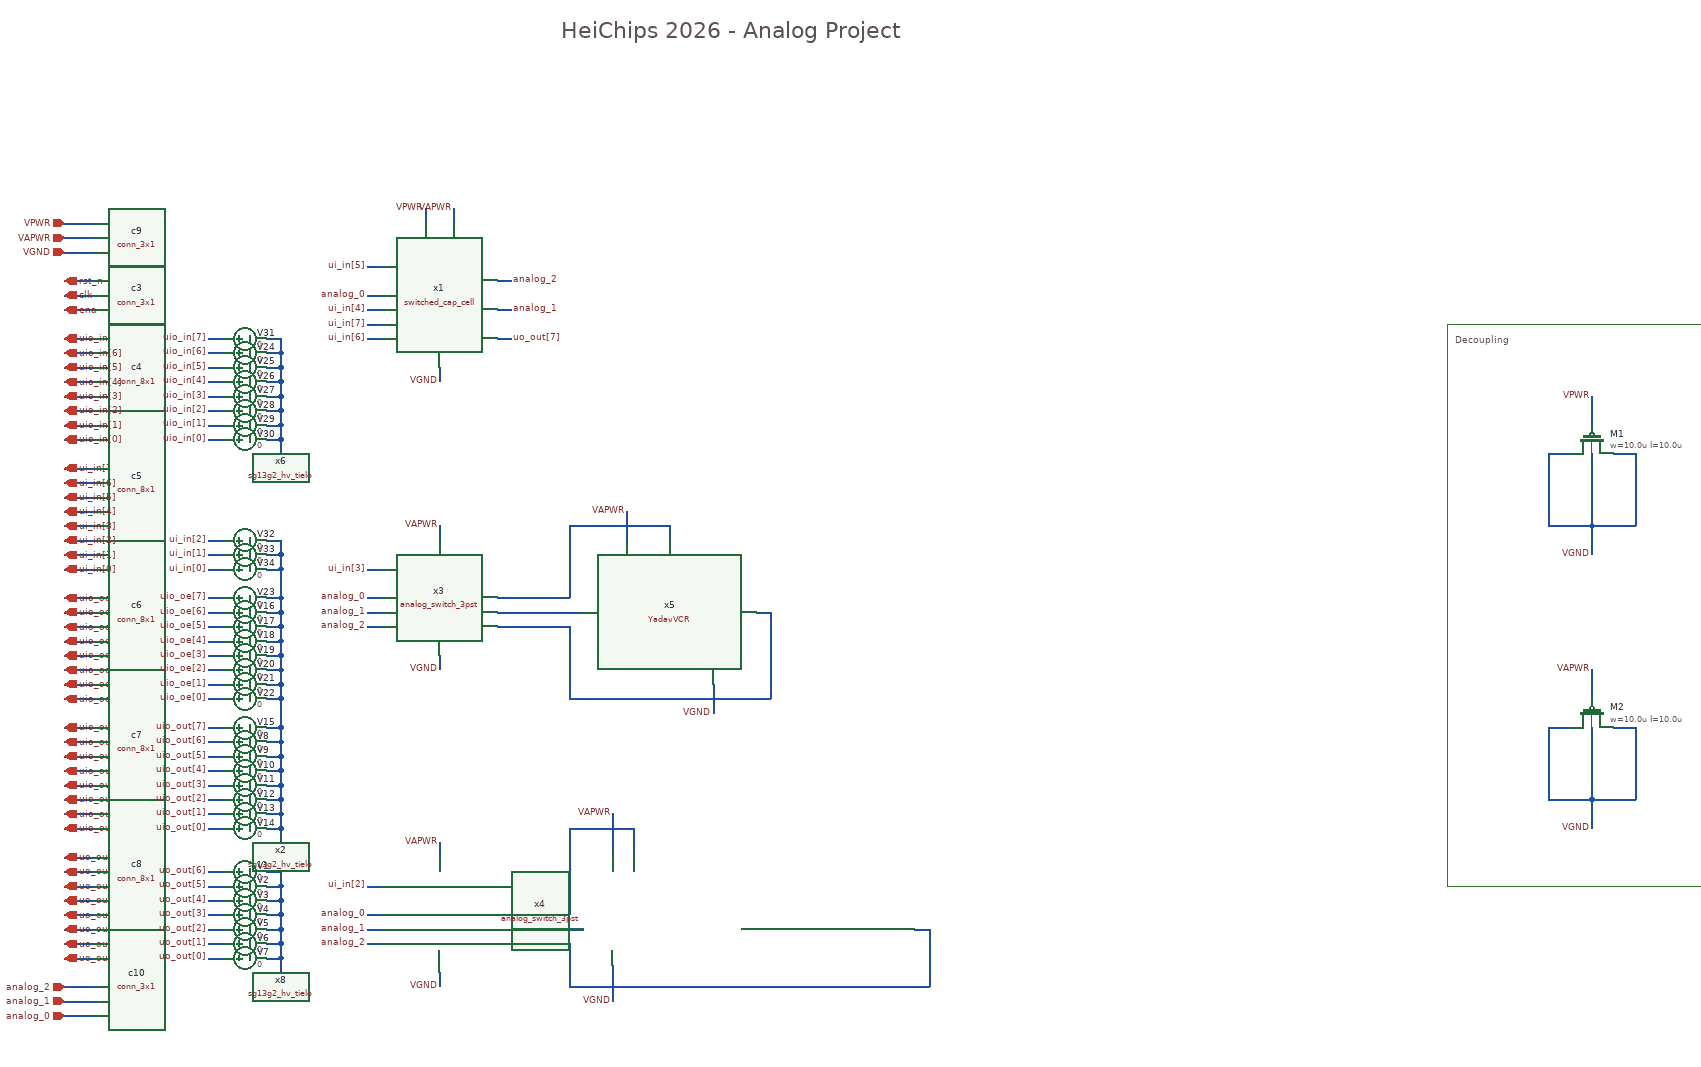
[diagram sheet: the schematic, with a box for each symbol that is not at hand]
v {xschem version=3.4.8RC file_version=1.3}
G {}
K {}
V {}
S {}
F {}
E {}
P 4 1 2050 -1280 {}
P 4 5 2060 -1280 2460 -1280 2460 -500 2060 -500 2060 -1280 {fill = false
dash = 16}
T {HeiChips 2026 - Analog Project} 830 -1700 0 0 1 1 {}
T {Decoupling} 2070 -1270 0 0 0.4 0.4 {}
N 2260 -800 2260 -760 {lab=VAPWR
spice_ignore=true}
N 2200 -720 2230 -720 {lab=VGND
spice_ignore=true}
N 2200 -720 2200 -620 {lab=VGND
spice_ignore=true}
N 2260 -620 2320 -620 {lab=VGND
spice_ignore=true}
N 2320 -720 2320 -620 {lab=VGND
spice_ignore=true}
N 2290 -720 2320 -720 {lab=VGND
spice_ignore=true}
N 2260 -620 2260 -580 {lab=VGND
spice_ignore=true}
N 2260 -720 2260 -620 {lab=VGND
spice_ignore=true}
N 2200 -620 2260 -620 {lab=VGND
spice_ignore=true}
N 140 -1320 180 -1320 {lab=clk}
N 140 -1300 180 -1300 {lab=ena}
N 140 -1340 180 -1340 {lab=rst_n}
N 140 -1260 180 -1260 {lab=uio_in[7]}
N 140 -1240 180 -1240 {lab=uio_in[6]}
N 140 -1220 180 -1220 {lab=uio_in[5]}
N 140 -1200 180 -1200 {lab=uio_in[4]}
N 140 -1180 180 -1180 {lab=uio_in[3]}
N 140 -1160 180 -1160 {lab=uio_in[2]}
N 140 -1140 180 -1140 {lab=uio_in[1]}
N 140 -1120 180 -1120 {lab=uio_in[0]}
N 140 -1080 180 -1080 {lab=ui_in[7]}
N 140 -1060 180 -1060 {lab=ui_in[6]}
N 140 -1040 180 -1040 {lab=ui_in[5]}
N 140 -1020 180 -1020 {lab=ui_in[4]}
N 140 -1000 180 -1000 {lab=ui_in[3]}
N 140 -980 180 -980 {lab=ui_in[2]}
N 140 -960 180 -960 {lab=ui_in[1]}
N 140 -940 180 -940 {lab=ui_in[0]}
N 140 -900 180 -900 {lab=uio_oe[7]}
N 140 -880 180 -880 {lab=uio_oe[6]}
N 140 -860 180 -860 {lab=uio_oe[5]}
N 140 -840 180 -840 {lab=uio_oe[4]}
N 140 -820 180 -820 {lab=uio_oe[3]}
N 140 -800 180 -800 {lab=uio_oe[2]}
N 140 -780 180 -780 {lab=uio_oe[1]}
N 140 -760 180 -760 {lab=uio_oe[0]}
N 140 -720 180 -720 {lab=uio_out[7]}
N 140 -700 180 -700 {lab=uio_out[6]}
N 140 -680 180 -680 {lab=uio_out[5]}
N 140 -660 180 -660 {lab=uio_out[4]}
N 140 -640 180 -640 {lab=uio_out[3]}
N 140 -620 180 -620 {lab=uio_out[2]}
N 140 -600 180 -600 {lab=uio_out[1]}
N 140 -580 180 -580 {lab=uio_out[0]}
N 140 -540 180 -540 {lab=uo_out[7]}
N 140 -520 180 -520 {lab=uo_out[6]}
N 140 -500 180 -500 {lab=uo_out[5]}
N 140 -480 180 -480 {lab=uo_out[4]}
N 140 -460 180 -460 {lab=uo_out[3]}
N 140 -440 180 -440 {lab=uo_out[2]}
N 140 -420 180 -420 {lab=uo_out[1]}
N 140 -400 180 -400 {lab=uo_out[0]}
N 140 -1400 180 -1400 {lab=VAPWR}
N 140 -1380 180 -1380 {lab=VGND}
N 140 -1420 180 -1420 {lab=VPWR}
N 140 -360 180 -360 {lab=analog_2}
N 140 -340 180 -340 {lab=analog_1}
N 140 -320 180 -320 {lab=analog_0}
N 2260 -1180 2260 -1140 {lab=VPWR
spice_ignore=true}
N 2200 -1100 2230 -1100 {lab=VGND
spice_ignore=true}
N 2200 -1100 2200 -1000 {lab=VGND
spice_ignore=true}
N 2260 -1000 2320 -1000 {lab=VGND
spice_ignore=true}
N 2320 -1100 2320 -1000 {lab=VGND
spice_ignore=true}
N 2290 -1100 2320 -1100 {lab=VGND
spice_ignore=true}
N 2260 -1000 2260 -960 {lab=VGND
spice_ignore=true}
N 2260 -1100 2260 -1000 {lab=VGND
spice_ignore=true}
N 2200 -1000 2260 -1000 {lab=VGND
spice_ignore=true}
N 560 -1360 580 -1360 {lab=ui_in[5]}
N 560 -1300 580 -1300 {lab=ui_in[4]}
N 560 -1280 580 -1280 {lab=ui_in[7]}
N 560 -1260 580 -1260 {lab=ui_in[6]}
N 740 -1260 760 -1260 {lab=uo_out[7]}
N 640 -1440 640 -1420 {lab=VPWR}
N 680 -1440 680 -1420 {lab=VAPWR}
N 660 -1220 660 -1200 {lab=VGND}
N 740 -1340 760 -1340 {lab=analog_2}
N 740 -1300 760 -1300 {lab=analog_1}
N 920 -1020 920 -980 {lab=VAPWR}
N 1040 -780 1040 -740 {lab=VGND}
N 840 -760 1120 -760 {lab=#net1}
N 1100 -880 1120 -880 {lab=#net1}
N 1120 -880 1120 -760 {lab=#net1}
N 740 -880 860 -880 {lab=#net2}
N 660 -1000 660 -980 {lab=VAPWR}
N 660 -820 660 -800 {lab=VGND}
N 560 -860 580 -860 {lab=analog_2}
N 560 -880 580 -880 {lab=analog_1}
N 560 -940 580 -940 {lab=ui_in[3]}
N 560 -900 580 -900 {lab=analog_0}
N 740 -900 840 -900 {lab=#net3}
N 840 -1000 840 -900 {lab=#net3}
N 840 -1000 980 -1000 {lab=#net3}
N 980 -1000 980 -980 {lab=#net3}
N 740 -860 840 -860 {lab=#net1}
N 840 -860 840 -760 {lab=#net1}
N 660 -560 660 -540 {lab=VAPWR
spice_ignore=true}
N 660 -380 660 -360 {lab=VGND
spice_ignore=true}
N 560 -420 580 -420 {lab=analog_2
spice_ignore=true}
N 560 -440 580 -440 {lab=analog_1
spice_ignore=true}
N 560 -500 580 -500 {lab=ui_in[2]
spice_ignore=true}
N 560 -460 580 -460 {lab=analog_0
spice_ignore=true}
N 740 -440 860 -440 {lab=#net4
spice_ignore=true}
N 740 -420 840 -420 {lab=#net5
spice_ignore=true}
N 840 -420 840 -360 {lab=#net5
spice_ignore=true}
N 840 -360 1340 -360 {lab=#net5
spice_ignore=true}
N 1340 -440 1340 -360 {lab=#net5
spice_ignore=true}
N 1320 -440 1340 -440 {lab=#net5
spice_ignore=true}
N 740 -460 840 -460 {lab=#net6
spice_ignore=true}
N 840 -580 840 -460 {lab=#net6
spice_ignore=true}
N 840 -580 930 -580 {lab=#net6
spice_ignore=true}
N 930 -580 930 -550 {lab=#net6
spice_ignore=true}
N 900 -390 900 -340 {lab=VGND
spice_ignore=true}
N 900 -600 900 -550 {lab=VAPWR
spice_ignore=true}
N 560 -1320 580 -1320 {lab=analog_0}
N 340 -400 360 -400 {lab=uo_out[0]}
N 340 -420 360 -420 {lab=uo_out[1]}
N 340 -440 360 -440 {lab=uo_out[2]}
N 340 -460 360 -460 {lab=uo_out[3]}
N 340 -480 360 -480 {lab=uo_out[4]}
N 340 -500 360 -500 {lab=uo_out[5]}
N 340 -520 360 -520 {lab=uo_out[6]}
N 420 -520 440 -520 {lab=#net4}
N 440 -520 440 -500 {lab=#net4}
N 420 -500 440 -500 {lab=#net4}
N 440 -500 440 -480 {lab=#net4}
N 420 -480 440 -480 {lab=#net4}
N 440 -480 440 -460 {lab=#net4}
N 420 -460 440 -460 {lab=#net4}
N 440 -460 440 -440 {lab=#net4}
N 420 -440 440 -440 {lab=#net4}
N 440 -440 440 -420 {lab=#net4}
N 420 -420 440 -420 {lab=#net4}
N 440 -420 440 -400 {lab=#net4}
N 420 -400 440 -400 {lab=#net4}
N 440 -400 440 -380 {lab=#net4}
N 340 -580 360 -580 {lab=uio_out[0]}
N 340 -600 360 -600 {lab=uio_out[1]}
N 340 -620 360 -620 {lab=uio_out[2]}
N 340 -640 360 -640 {lab=uio_out[3]}
N 340 -660 360 -660 {lab=uio_out[4]}
N 340 -680 360 -680 {lab=uio_out[5]}
N 340 -700 360 -700 {lab=uio_out[6]}
N 420 -700 440 -700 {lab=#net5}
N 440 -700 440 -680 {lab=#net5}
N 420 -680 440 -680 {lab=#net5}
N 440 -680 440 -660 {lab=#net5}
N 420 -660 440 -660 {lab=#net5}
N 440 -660 440 -640 {lab=#net5}
N 420 -640 440 -640 {lab=#net5}
N 440 -640 440 -620 {lab=#net5}
N 420 -620 440 -620 {lab=#net5}
N 440 -620 440 -600 {lab=#net5}
N 420 -600 440 -600 {lab=#net5}
N 440 -600 440 -580 {lab=#net5}
N 420 -580 440 -580 {lab=#net5}
N 440 -580 440 -560 {lab=#net5}
N 340 -720 360 -720 {lab=uio_out[7]}
N 420 -720 440 -720 {lab=#net5}
N 340 -1120 360 -1120 {lab=uio_in[0]}
N 340 -1140 360 -1140 {lab=uio_in[1]}
N 340 -1160 360 -1160 {lab=uio_in[2]}
N 340 -1180 360 -1180 {lab=uio_in[3]}
N 340 -1200 360 -1200 {lab=uio_in[4]}
N 340 -1220 360 -1220 {lab=uio_in[5]}
N 340 -1240 360 -1240 {lab=uio_in[6]}
N 420 -1240 440 -1240 {lab=#net6}
N 440 -1240 440 -1220 {lab=#net6}
N 420 -1220 440 -1220 {lab=#net6}
N 440 -1220 440 -1200 {lab=#net6}
N 420 -1200 440 -1200 {lab=#net6}
N 440 -1200 440 -1180 {lab=#net6}
N 420 -1180 440 -1180 {lab=#net6}
N 440 -1180 440 -1160 {lab=#net6}
N 420 -1160 440 -1160 {lab=#net6}
N 440 -1160 440 -1140 {lab=#net6}
N 420 -1140 440 -1140 {lab=#net6}
N 440 -1140 440 -1120 {lab=#net6}
N 420 -1120 440 -1120 {lab=#net6}
N 440 -1120 440 -1100 {lab=#net6}
N 340 -1260 360 -1260 {lab=uio_in[7]}
N 420 -1260 440 -1260 {lab=#net6}
N 440 -1260 440 -1240 {lab=#net6}
N 340 -760 360 -760 {lab=uio_oe[0]}
N 340 -780 360 -780 {lab=uio_oe[1]}
N 340 -800 360 -800 {lab=uio_oe[2]}
N 340 -820 360 -820 {lab=uio_oe[3]}
N 340 -840 360 -840 {lab=uio_oe[4]}
N 340 -860 360 -860 {lab=uio_oe[5]}
N 340 -880 360 -880 {lab=uio_oe[6]}
N 420 -880 440 -880 {lab=#net5}
N 440 -880 440 -860 {lab=#net5}
N 420 -860 440 -860 {lab=#net5}
N 440 -860 440 -840 {lab=#net5}
N 420 -840 440 -840 {lab=#net5}
N 440 -840 440 -820 {lab=#net5}
N 420 -820 440 -820 {lab=#net5}
N 440 -820 440 -800 {lab=#net5}
N 420 -800 440 -800 {lab=#net5}
N 440 -800 440 -780 {lab=#net5}
N 420 -780 440 -780 {lab=#net5}
N 440 -780 440 -760 {lab=#net5}
N 420 -760 440 -760 {lab=#net5}
N 440 -760 440 -720 {lab=#net5}
N 340 -900 360 -900 {lab=uio_oe[7]}
N 420 -900 440 -900 {lab=#net5}
N 440 -900 440 -880 {lab=#net5}
N 440 -720 440 -700 {lab=#net5}
N 340 -940 360 -940 {lab=ui_in[0]}
N 340 -960 360 -960 {lab=ui_in[1]}
N 340 -980 360 -980 {lab=ui_in[2]}
N 420 -980 440 -980 {lab=#net5}
N 440 -980 440 -960 {lab=#net5}
N 420 -960 440 -960 {lab=#net5}
N 440 -960 440 -940 {lab=#net5}
N 420 -940 440 -940 {lab=#net5}
N 440 -940 440 -900 {lab=#net5}
C {title-3.sym} 0 0 0 0 {name=l1 author="Simon Dorrer" rev=1.0 lock=true}
C {lab_pin.sym} 2260 -800 1 0 {name=p25 sig_type=std_logic lab=VAPWR
spice_ignore=true}
C {lab_pin.sym} 2260 -580 3 0 {name=p26 sig_type=std_logic lab=VGND
spice_ignore=true}
C {devices/ipin.sym} 140 -1340 2 1 {name=p30 lab=rst_n}
C {devices/ipin.sym} 140 -1320 2 1 {name=p31 lab=clk}
C {devices/ipin.sym} 140 -1300 2 1 {name=p32 lab=ena}
C {devices/ipin.sym} 140 -1260 2 1 {name=p33 lab=uio_in[7]}
C {conn_3x1.sym} 200 -1320 0 1 {name=c3 footprint=connector(3,1)}
C {conn_8x1.sym} 200 -1240 0 1 {name=c4 footprint=connector(8,1)}
C {devices/ipin.sym} 140 -1080 2 1 {name=p8 lab=ui_in[7]}
C {conn_8x1.sym} 200 -1060 0 1 {name=c5 footprint=connector(8,1)}
C {devices/opin.sym} 140 -900 2 0 {name=p18 lab=uio_oe[7]}
C {devices/opin.sym} 140 -880 2 0 {name=p27 lab=uio_oe[6]}
C {devices/opin.sym} 140 -860 2 0 {name=p28 lab=uio_oe[5]}
C {devices/opin.sym} 140 -840 2 0 {name=p29 lab=uio_oe[4]}
C {devices/opin.sym} 140 -820 2 0 {name=p41 lab=uio_oe[3]}
C {devices/opin.sym} 140 -800 2 0 {name=p42 lab=uio_oe[2]}
C {devices/opin.sym} 140 -780 2 0 {name=p43 lab=uio_oe[1]}
C {devices/opin.sym} 140 -760 2 0 {name=p44 lab=uio_oe[0]}
C {conn_8x1.sym} 200 -880 0 1 {name=c6 footprint=connector(8,1)}
C {devices/opin.sym} 140 -720 2 0 {name=p45 lab=uio_out[7]}
C {devices/opin.sym} 140 -700 2 0 {name=p46 lab=uio_out[6]}
C {devices/opin.sym} 140 -680 2 0 {name=p47 lab=uio_out[5]}
C {devices/opin.sym} 140 -660 2 0 {name=p48 lab=uio_out[4]}
C {devices/opin.sym} 140 -640 2 0 {name=p49 lab=uio_out[3]}
C {devices/opin.sym} 140 -620 2 0 {name=p50 lab=uio_out[2]}
C {devices/opin.sym} 140 -600 2 0 {name=p51 lab=uio_out[1]}
C {devices/opin.sym} 140 -580 2 0 {name=p52 lab=uio_out[0]}
C {conn_8x1.sym} 200 -700 0 1 {name=c7 footprint=connector(8,1)}
C {devices/opin.sym} 140 -540 2 0 {name=p53 lab=uo_out[7]}
C {devices/opin.sym} 140 -520 2 0 {name=p54 lab=uo_out[6]}
C {devices/opin.sym} 140 -500 2 0 {name=p55 lab=uo_out[5]}
C {devices/opin.sym} 140 -480 2 0 {name=p56 lab=uo_out[4]}
C {devices/opin.sym} 140 -460 2 0 {name=p57 lab=uo_out[3]}
C {devices/opin.sym} 140 -440 2 0 {name=p58 lab=uo_out[2]}
C {devices/opin.sym} 140 -420 2 0 {name=p59 lab=uo_out[1]}
C {devices/opin.sym} 140 -400 2 0 {name=p60 lab=uo_out[0]}
C {conn_8x1.sym} 200 -520 0 1 {name=c8 footprint=connector(8,1)}
C {conn_3x1.sym} 200 -1400 0 1 {name=c9 footprint=connector(3,1)}
C {devices/iopin.sym} 140 -1420 2 0 {name=p61 lab=VPWR}
C {devices/iopin.sym} 140 -1380 2 0 {name=p62 lab=VGND}
C {devices/iopin.sym} 140 -1400 2 0 {name=p63 lab=VAPWR}
C {devices/ipin.sym} 140 -1060 2 1 {name=p9 lab=ui_in[6]}
C {devices/ipin.sym} 140 -1040 2 1 {name=p12 lab=ui_in[5]}
C {devices/ipin.sym} 140 -1020 2 1 {name=p13 lab=ui_in[4]}
C {devices/ipin.sym} 140 -1000 2 1 {name=p14 lab=ui_in[3]}
C {devices/ipin.sym} 140 -980 2 1 {name=p15 lab=ui_in[2]}
C {devices/ipin.sym} 140 -960 2 1 {name=p16 lab=ui_in[1]}
C {devices/ipin.sym} 140 -940 2 1 {name=p17 lab=ui_in[0]}
C {devices/ipin.sym} 140 -1240 2 1 {name=p34 lab=uio_in[6]}
C {devices/ipin.sym} 140 -1220 2 1 {name=p35 lab=uio_in[5]}
C {devices/ipin.sym} 140 -1200 2 1 {name=p36 lab=uio_in[4]}
C {devices/ipin.sym} 140 -1180 2 1 {name=p37 lab=uio_in[3]}
C {devices/ipin.sym} 140 -1160 2 1 {name=p38 lab=uio_in[2]}
C {devices/ipin.sym} 140 -1140 2 1 {name=p39 lab=uio_in[1]}
C {devices/ipin.sym} 140 -1120 2 1 {name=p40 lab=uio_in[0]}
C {conn_3x1.sym} 200 -340 0 1 {name=c10 footprint=connector(3,1)}
C {devices/iopin.sym} 140 -360 2 0 {name=p64 lab=analog_2}
C {devices/iopin.sym} 140 -340 2 0 {name=p65 lab=analog_1}
C {devices/iopin.sym} 140 -320 2 0 {name=p66 lab=analog_0}
C {lab_pin.sym} 2260 -1180 1 0 {name=p3 sig_type=std_logic lab=VPWR
spice_ignore=true}
C {lab_pin.sym} 2260 -960 3 0 {name=p4 sig_type=std_logic lab=VGND
spice_ignore=true}
C {sg13cmos5l_pr/sg13_lv_pmos.sym} 2260 -1120 1 0 {name=M1
l=10.0u
w=10.0u
ng=1
m=1
mm_ok=1
model=sg13_lv_pmos
spiceprefix=X
spice_ignore=true}
C {sg13cmos5l_pr/sg13_lv_pmos.sym} 2260 -740 1 0 {name=M2
l=10.0u
w=10.0u
ng=1
m=1
mm_ok=1
model=sg13_lv_pmos
spiceprefix=X
spice_ignore=true}
C {lab_pin.sym} 760 -1340 0 1 {name=p6 sig_type=std_logic lab=analog_2}
C {lab_pin.sym} 760 -1300 0 1 {name=p10 sig_type=std_logic lab=analog_1}
C {switched_cap_cell.sym} 660 -1320 0 0 {name=x1}
C {YadavVCR.sym} 980 -880 0 0 {name=x5}
C {lab_pin.sym} 560 -1300 0 0 {name=p20 sig_type=std_logic lab=ui_in[4]}
C {lab_pin.sym} 560 -1360 0 0 {name=p21 sig_type=std_logic lab=ui_in[5]}
C {lab_pin.sym} 560 -1260 0 0 {name=p22 sig_type=std_logic lab=ui_in[6]}
C {lab_pin.sym} 560 -1280 0 0 {name=p23 sig_type=std_logic lab=ui_in[7]}
C {lab_pin.sym} 560 -1320 0 0 {name=p24 sig_type=std_logic lab=analog_0}
C {lab_pin.sym} 760 -1260 0 1 {name=p67 sig_type=std_logic lab=uo_out[7]}
C {lab_pin.sym} 660 -1200 3 0 {name=p68 sig_type=std_logic lab=VGND}
C {lab_pin.sym} 680 -1440 1 0 {name=p69 sig_type=std_logic lab=VAPWR}
C {lab_pin.sym} 640 -1440 1 0 {name=p70 sig_type=std_logic lab=VPWR}
C {lab_pin.sym} 1040 -740 3 0 {name=p11 sig_type=std_logic lab=VGND}
C {lab_pin.sym} 920 -1020 1 0 {name=p19 sig_type=std_logic lab=VAPWR}
C {lab_pin.sym} 660 -800 3 0 {name=p1 sig_type=std_logic lab=VGND}
C {lab_pin.sym} 660 -1000 1 0 {name=p2 sig_type=std_logic lab=VAPWR}
C {lab_pin.sym} 560 -860 0 0 {name=p5 sig_type=std_logic lab=analog_2}
C {lab_pin.sym} 560 -880 0 0 {name=p7 sig_type=std_logic lab=analog_1}
C {lab_pin.sym} 560 -500 0 0 {name=p71 sig_type=std_logic lab=ui_in[2]
spice_ignore=true}
C {analog_switch_3pst.sym} 660 -900 0 0 {name=x3}
C {lab_pin.sym} 560 -900 0 0 {name=p72 sig_type=std_logic lab=analog_0}
C {lab_pin.sym} 660 -360 3 0 {name=p73 sig_type=std_logic lab=VGND
spice_ignore=true}
C {lab_pin.sym} 660 -560 1 0 {name=p74 sig_type=std_logic lab=VAPWR
spice_ignore=true}
C {lab_pin.sym} 560 -420 0 0 {name=p75 sig_type=std_logic lab=analog_2
spice_ignore=true}
C {lab_pin.sym} 560 -440 0 0 {name=p76 sig_type=std_logic lab=analog_1
spice_ignore=true}
C {lab_pin.sym} 560 -940 0 0 {name=p77 sig_type=std_logic lab=ui_in[3]}
C {analog_switch_3pst.sym} 660 -460 0 0 {name=x4
spice_ignore=true}
C {lab_pin.sym} 560 -460 0 0 {name=p78 sig_type=std_logic lab=analog_0
spice_ignore=true}
C {lab_pin.sym} 900 -340 3 0 {name=p79 sig_type=std_logic lab=VGND
spice_ignore=true}
C {lab_pin.sym} 900 -600 1 0 {name=p80 sig_type=std_logic lab=VAPWR
spice_ignore=true}
C {lab_pin.sym} 340 -980 0 0 {name=p81 sig_type=std_logic lab=ui_in[2]}
C {lab_pin.sym} 340 -960 0 0 {name=p82 sig_type=std_logic lab=ui_in[1]}
C {lab_pin.sym} 340 -940 0 0 {name=p83 sig_type=std_logic lab=ui_in[0]}
C {lab_pin.sym} 340 -520 0 0 {name=p84 sig_type=std_logic lab=uo_out[6]}
C {lab_pin.sym} 340 -500 0 0 {name=p85 sig_type=std_logic lab=uo_out[5]}
C {lab_pin.sym} 340 -480 0 0 {name=p86 sig_type=std_logic lab=uo_out[4]}
C {lab_pin.sym} 340 -460 0 0 {name=p87 sig_type=std_logic lab=uo_out[3]}
C {lab_pin.sym} 340 -440 0 0 {name=p88 sig_type=std_logic lab=uo_out[2]}
C {lab_pin.sym} 340 -420 0 0 {name=p89 sig_type=std_logic lab=uo_out[1]}
C {lab_pin.sym} 340 -400 0 0 {name=p90 sig_type=std_logic lab=uo_out[0]}
C {lab_pin.sym} 340 -700 0 0 {name=p91 sig_type=std_logic lab=uio_out[6]}
C {lab_pin.sym} 340 -680 0 0 {name=p92 sig_type=std_logic lab=uio_out[5]}
C {lab_pin.sym} 340 -660 0 0 {name=p93 sig_type=std_logic lab=uio_out[4]}
C {lab_pin.sym} 340 -640 0 0 {name=p94 sig_type=std_logic lab=uio_out[3]}
C {lab_pin.sym} 340 -620 0 0 {name=p95 sig_type=std_logic lab=uio_out[2]}
C {lab_pin.sym} 340 -600 0 0 {name=p96 sig_type=std_logic lab=uio_out[1]}
C {lab_pin.sym} 340 -580 0 0 {name=p97 sig_type=std_logic lab=uio_out[0]}
C {lab_pin.sym} 340 -720 0 0 {name=p98 sig_type=std_logic lab=uio_out[7]}
C {lab_pin.sym} 340 -1160 0 0 {name=p99 sig_type=std_logic lab=uio_in[2]}
C {lab_pin.sym} 340 -1140 0 0 {name=p100 sig_type=std_logic lab=uio_in[1]}
C {lab_pin.sym} 340 -1120 0 0 {name=p101 sig_type=std_logic lab=uio_in[0]}
C {lab_pin.sym} 340 -1240 0 0 {name=p102 sig_type=std_logic lab=uio_in[6]}
C {lab_pin.sym} 340 -1220 0 0 {name=p103 sig_type=std_logic lab=uio_in[5]}
C {lab_pin.sym} 340 -1200 0 0 {name=p104 sig_type=std_logic lab=uio_in[4]}
C {lab_pin.sym} 340 -1260 0 0 {name=p105 sig_type=std_logic lab=uio_in[7]}
C {lab_pin.sym} 340 -1180 0 0 {name=p106 sig_type=std_logic lab=uio_in[3]}
C {lab_pin.sym} 340 -800 0 0 {name=p107 sig_type=std_logic lab=uio_oe[2]}
C {lab_pin.sym} 340 -780 0 0 {name=p108 sig_type=std_logic lab=uio_oe[1]}
C {lab_pin.sym} 340 -760 0 0 {name=p109 sig_type=std_logic lab=uio_oe[0]}
C {lab_pin.sym} 340 -880 0 0 {name=p110 sig_type=std_logic lab=uio_oe[6]}
C {lab_pin.sym} 340 -860 0 0 {name=p111 sig_type=std_logic lab=uio_oe[5]}
C {lab_pin.sym} 340 -840 0 0 {name=p112 sig_type=std_logic lab=uio_oe[4]}
C {lab_pin.sym} 340 -900 0 0 {name=p113 sig_type=std_logic lab=uio_oe[7]}
C {lab_pin.sym} 340 -820 0 0 {name=p114 sig_type=std_logic lab=uio_oe[3]}
C {sg13g2_hv_tielo.sym} 440 -380 0 0 {name=x8 VDD=VDD VSS=VSS prefix=sg13g2_hv_ }
C {sg13g2_hv_tielo.sym} 440 -560 0 0 {name=x2 VDD=VDD VSS=VSS prefix=sg13g2_hv_ }
C {sg13g2_hv_tielo.sym} 440 -1100 0 0 {name=x6 VDD=VDD VSS=VSS prefix=sg13g2_hv_ }
C {vsource.sym} 390 -520 3 0 {name=V1 value=0 savecurrent=false}
C {vsource.sym} 390 -500 3 0 {name=V2 value=0 savecurrent=false}
C {vsource.sym} 390 -480 3 0 {name=V3 value=0 savecurrent=false}
C {vsource.sym} 390 -460 3 0 {name=V4 value=0 savecurrent=false}
C {vsource.sym} 390 -440 3 0 {name=V5 value=0 savecurrent=false}
C {vsource.sym} 390 -420 3 0 {name=V6 value=0 savecurrent=false}
C {vsource.sym} 390 -400 3 0 {name=V7 value=0 savecurrent=false}
C {vsource.sym} 390 -700 3 0 {name=V8 value=0 savecurrent=false}
C {vsource.sym} 390 -680 3 0 {name=V9 value=0 savecurrent=false}
C {vsource.sym} 390 -660 3 0 {name=V10 value=0 savecurrent=false}
C {vsource.sym} 390 -640 3 0 {name=V11 value=0 savecurrent=false}
C {vsource.sym} 390 -620 3 0 {name=V12 value=0 savecurrent=false}
C {vsource.sym} 390 -600 3 0 {name=V13 value=0 savecurrent=false}
C {vsource.sym} 390 -580 3 0 {name=V14 value=0 savecurrent=false}
C {vsource.sym} 390 -720 3 0 {name=V15 value=0 savecurrent=false}
C {vsource.sym} 390 -880 3 0 {name=V16 value=0 savecurrent=false}
C {vsource.sym} 390 -860 3 0 {name=V17 value=0 savecurrent=false}
C {vsource.sym} 390 -840 3 0 {name=V18 value=0 savecurrent=false}
C {vsource.sym} 390 -820 3 0 {name=V19 value=0 savecurrent=false}
C {vsource.sym} 390 -800 3 0 {name=V20 value=0 savecurrent=false}
C {vsource.sym} 390 -780 3 0 {name=V21 value=0 savecurrent=false}
C {vsource.sym} 390 -760 3 0 {name=V22 value=0 savecurrent=false}
C {vsource.sym} 390 -900 3 0 {name=V23 value=0 savecurrent=false}
C {vsource.sym} 390 -1240 3 0 {name=V24 value=0 savecurrent=false}
C {vsource.sym} 390 -1220 3 0 {name=V25 value=0 savecurrent=false}
C {vsource.sym} 390 -1200 3 0 {name=V26 value=0 savecurrent=false}
C {vsource.sym} 390 -1180 3 0 {name=V27 value=0 savecurrent=false}
C {vsource.sym} 390 -1160 3 0 {name=V28 value=0 savecurrent=false}
C {vsource.sym} 390 -1140 3 0 {name=V29 value=0 savecurrent=false}
C {vsource.sym} 390 -1120 3 0 {name=V30 value=0 savecurrent=false}
C {vsource.sym} 390 -1260 3 0 {name=V31 value=0 savecurrent=false}
C {vsource.sym} 390 -980 3 0 {name=V32 value=0 savecurrent=false}
C {vsource.sym} 390 -960 3 0 {name=V33 value=0 savecurrent=false}
C {vsource.sym} 390 -940 3 0 {name=V34 value=0 savecurrent=false}
